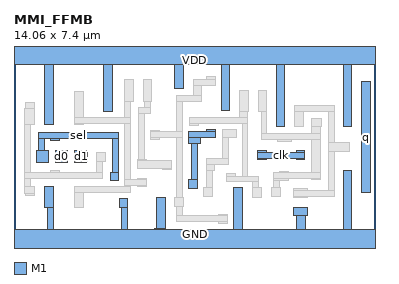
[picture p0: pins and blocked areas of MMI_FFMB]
MACRO MMI_FFMB
	CLASS CORE ;
	FOREIGN MMI_FFMB 0 0 ;
	SIZE 14.06 BY 7.4 ;
	SYMMETRY X Y ;
	SITE CORE1 ;
	PIN d0
		DIRECTION input ;
		USE SIGNAL ;
		PORT
			LAYER M1 ;
			RECT 1.625 3.105 2.075 3.555 ;
		END
		AntennaGateArea 0.4968 ;
	END d0
	PIN sel
		DIRECTION input ;
		USE SIGNAL ;
		PORT
			LAYER M1 ;
			RECT 1.44 4.265 1.78 4.275 ;
			LAYER M1 ;
			RECT 0.97 4.035 4.08 4.265 ;
			LAYER M1 ;
			RECT 0.97 3.555 1.2 4.035 ;
			LAYER M1 ;
			RECT 1.44 3.935 1.78 4.035 ;
			LAYER M1 ;
			RECT 0.875 3.105 1.325 3.555 ;
			LAYER M1 ;
			RECT 3.85 2.72 4.08 4.035 ;
			LAYER M1 ;
			RECT 3.74 2.38 4.08 2.72 ;
		END
		AntennaGateArea 0.7452 ;
	END sel
	PIN GND
		DIRECTION inout ;
		USE GROUND ;
		PORT
			LAYER M1 ;
			RECT 1.2 1.34 1.54 2.18 ;
			LAYER M1 ;
			RECT 4.09 1.345 4.43 1.685 ;
			LAYER M1 ;
			RECT 1.31 0.5 1.54 1.34 ;
			LAYER M1 ;
			RECT 4.2 0.5 4.43 1.345 ;
			LAYER M1 ;
			RECT 5.545 0.51 5.885 1.75 ;
			LAYER M1 ;
			RECT 5.485 0.5 5.885 0.51 ;
			LAYER M1 ;
			RECT 8.565 0.5 8.905 2.105 ;
			LAYER M1 ;
			RECT 10.885 1.015 11.425 1.355 ;
			LAYER M1 ;
			RECT 10.995 0.5 11.335 1.015 ;
			LAYER M1 ;
			RECT 12.82 0.5 13.16 2.775 ;
			LAYER M1 ;
			RECT 0 -0.5 14.06 0.5 ;
		END
	END GND
	PIN q
		DIRECTION output ;
		USE SIGNAL ;
		PORT
			LAYER M1 ;
			RECT 13.54 1.935 13.88 6.24 ;
		END
		AntennaDiffArea 1.3248 ;
	END q
	PIN d1
		DIRECTION input ;
		USE SIGNAL ;
		PORT
			LAYER M1 ;
			RECT 2.365 3.485 2.815 3.555 ;
			LAYER M1 ;
			RECT 2.365 3.145 2.88 3.485 ;
			LAYER M1 ;
			RECT 2.365 3.105 2.815 3.145 ;
		END
		AntennaGateArea 0.4968 ;
	END d1
	PIN VDD
		DIRECTION inout ;
		USE POWER ;
		PORT
			LAYER M1 ;
			RECT 0 6.9 14.06 7.9 ;
			LAYER M1 ;
			RECT 1.2 4.585 1.54 6.9 ;
			LAYER M1 ;
			RECT 3.5 5.075 3.84 6.9 ;
			LAYER M1 ;
			RECT 6.26 5.975 6.6 6.9 ;
			LAYER M1 ;
			RECT 8.07 5.105 8.41 6.9 ;
			LAYER M1 ;
			RECT 10.21 4.48 10.55 6.9 ;
			LAYER M1 ;
			RECT 12.82 4.48 13.16 6.9 ;
		END
	END VDD
	PIN clk
		DIRECTION input ;
		USE CLOCK ;
		PORT
			LAYER M1 ;
			RECT 7.5 4.29 7.84 4.4 ;
			LAYER M1 ;
			RECT 6.805 4.06 7.84 4.29 ;
			LAYER M1 ;
			RECT 6.805 3.84 7.255 4.06 ;
			LAYER M1 ;
			RECT 6.915 2.435 7.145 3.84 ;
			LAYER M1 ;
			RECT 9.475 3.475 9.815 3.55 ;
			LAYER M1 ;
			RECT 10.99 3.475 11.33 3.565 ;
			LAYER M1 ;
			RECT 9.475 3.245 11.33 3.475 ;
			LAYER M1 ;
			RECT 9.475 3.21 9.815 3.245 ;
			LAYER M1 ;
			RECT 10.99 3.225 11.33 3.245 ;
			LAYER M1 ;
			RECT 6.805 2.095 7.145 2.435 ;
		END
		AntennaGateArea 0.6408 ;
	END clk
	OBS
		LAYER M1 ;
		RECT 0.44 5.21 0.78 5.425 ;
		LAYER M1 ;
		RECT 0.415 4.585 0.78 5.21 ;
		LAYER M1 ;
		RECT 2.35 4.84 2.69 5.865 ;
		LAYER M1 ;
		RECT 4.31 5.475 4.65 6.315 ;
		LAYER M1 ;
		RECT 5.03 5.475 5.37 6.315 ;
		LAYER M1 ;
		RECT 7.5 6.32 7.84 6.43 ;
		LAYER M1 ;
		RECT 6.98 6.09 7.84 6.32 ;
		LAYER M1 ;
		RECT 6.98 5.705 7.32 6.09 ;
		LAYER M1 ;
		RECT 6.345 5.475 7.32 5.705 ;
		LAYER M1 ;
		RECT 4.31 4.84 4.54 5.475 ;
		LAYER M1 ;
		RECT 5.07 5.225 5.3 5.475 ;
		LAYER M1 ;
		RECT 2.35 4.61 4.54 4.84 ;
		LAYER M1 ;
		RECT 2.35 4.585 2.69 4.61 ;
		LAYER M1 ;
		RECT 0.415 2.72 0.645 4.585 ;
		LAYER M1 ;
		RECT 3.225 3.135 3.565 3.475 ;
		LAYER M1 ;
		RECT 1.44 2.72 1.78 2.8 ;
		LAYER M1 ;
		RECT 3.225 2.72 3.455 3.135 ;
		LAYER M1 ;
		RECT 0.415 2.49 3.455 2.72 ;
		LAYER M1 ;
		RECT 0.415 2.18 0.645 2.49 ;
		LAYER M1 ;
		RECT 1.44 2.46 1.78 2.49 ;
		LAYER M1 ;
		RECT 4.31 2.435 4.54 4.61 ;
		LAYER M1 ;
		RECT 4.845 4.995 5.3 5.225 ;
		LAYER M1 ;
		RECT 4.845 3.21 5.075 4.995 ;
		LAYER M1 ;
		RECT 5.31 4.29 5.65 4.35 ;
		LAYER M1 ;
		RECT 6.345 4.29 6.575 5.475 ;
		LAYER M1 ;
		RECT 8.79 5.075 9.13 5.915 ;
		LAYER M1 ;
		RECT 9.51 5.075 9.85 5.915 ;
		LAYER M1 ;
		RECT 6.83 4.86 7.17 4.865 ;
		LAYER M1 ;
		RECT 8.79 4.86 9.11 5.075 ;
		LAYER M1 ;
		RECT 6.83 4.63 9.11 4.86 ;
		LAYER M1 ;
		RECT 6.83 4.525 7.17 4.63 ;
		LAYER M1 ;
		RECT 5.31 4.06 6.575 4.29 ;
		LAYER M1 ;
		RECT 5.31 4.01 5.65 4.06 ;
		LAYER M1 ;
		RECT 4.815 3.165 5.155 3.21 ;
		LAYER M1 ;
		RECT 5.775 3.165 6.115 3.17 ;
		LAYER M1 ;
		RECT 4.815 2.87 6.115 3.165 ;
		LAYER M1 ;
		RECT 5.775 2.83 6.115 2.87 ;
		LAYER M1 ;
		RECT 4.815 2.435 5.155 2.49 ;
		LAYER M1 ;
		RECT 4.31 2.205 5.155 2.435 ;
		LAYER M1 ;
		RECT 0.415 1.905 0.78 2.18 ;
		LAYER M1 ;
		RECT 0.44 1.8 0.78 1.905 ;
		LAYER M1 ;
		RECT 2.35 2.15 2.69 2.18 ;
		LAYER M1 ;
		RECT 4.31 2.15 4.54 2.205 ;
		LAYER M1 ;
		RECT 4.815 2.15 5.155 2.205 ;
		LAYER M1 ;
		RECT 2.35 1.92 4.54 2.15 ;
		LAYER M1 ;
		RECT 2.35 1.34 2.69 1.92 ;
		LAYER M1 ;
		RECT 6.345 1.75 6.575 4.06 ;
		LAYER M1 ;
		RECT 8.13 4.06 8.65 4.4 ;
		LAYER M1 ;
		RECT 8.13 3.255 8.36 4.06 ;
		LAYER M1 ;
		RECT 7.485 3.025 8.36 3.255 ;
		LAYER M1 ;
		RECT 7.485 2.77 7.825 3.025 ;
		LAYER M1 ;
		RECT 7.485 2.105 7.715 2.77 ;
		LAYER M1 ;
		RECT 8.285 2.57 8.625 2.68 ;
		LAYER M1 ;
		RECT 8.88 2.57 9.11 4.63 ;
		LAYER M1 ;
		RECT 9.62 4.235 9.85 5.075 ;
		LAYER M1 ;
		RECT 10.93 5.315 11.27 5.32 ;
		LAYER M1 ;
		RECT 10.93 5.085 12.495 5.315 ;
		LAYER M1 ;
		RECT 10.93 4.48 11.27 5.085 ;
		LAYER M1 ;
		RECT 11.58 4.48 11.97 4.82 ;
		LAYER M1 ;
		RECT 11.58 4.235 11.92 4.48 ;
		LAYER M1 ;
		RECT 9.62 4.005 11.92 4.235 ;
		LAYER M1 ;
		RECT 10.275 3.895 10.79 4.005 ;
		LAYER M1 ;
		RECT 10.335 2.715 10.675 2.745 ;
		LAYER M1 ;
		RECT 11.58 2.715 11.92 4.005 ;
		LAYER M1 ;
		RECT 8.285 2.34 9.515 2.57 ;
		LAYER M1 ;
		RECT 9.285 2.105 9.515 2.34 ;
		LAYER M1 ;
		RECT 10.105 2.485 11.92 2.715 ;
		LAYER M1 ;
		RECT 10.105 2.405 10.675 2.485 ;
		LAYER M1 ;
		RECT 11.58 2.435 11.92 2.485 ;
		LAYER M1 ;
		RECT 12.265 3.865 12.495 5.085 ;
		LAYER M1 ;
		RECT 12.265 3.525 13.06 3.865 ;
		LAYER M1 ;
		RECT 10.105 2.105 10.335 2.405 ;
		LAYER M1 ;
		RECT 7.375 1.765 7.715 2.105 ;
		LAYER M1 ;
		RECT 6.265 1.37 6.605 1.75 ;
		LAYER M1 ;
		RECT 6.345 1.025 6.575 1.37 ;
		LAYER M1 ;
		RECT 7.97 1.025 8.31 1.07 ;
		LAYER M1 ;
		RECT 6.345 0.795 8.31 1.025 ;
		LAYER M1 ;
		RECT 7.97 0.73 8.31 0.795 ;
		LAYER M1 ;
		RECT 9.285 1.725 9.625 2.105 ;
		LAYER M1 ;
		RECT 10.045 1.765 10.385 2.105 ;
		LAYER M1 ;
		RECT 10.885 2.01 11.425 2.075 ;
		LAYER M1 ;
		RECT 12.265 2.01 12.495 3.525 ;
		LAYER M1 ;
		RECT 10.885 1.78 12.495 2.01 ;
		LAYER M1 ;
		RECT 10.885 1.735 11.425 1.78 ;
	END
END MMI_FFMB
